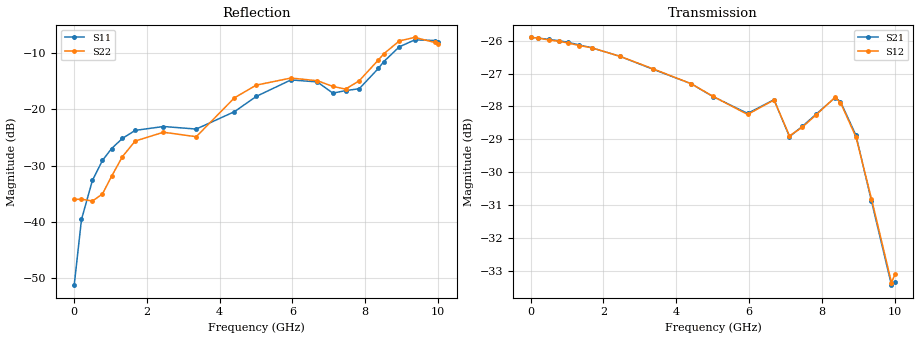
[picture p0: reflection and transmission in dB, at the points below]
! Device ID: PE43704
! Dir: z:\PE43704\PE43704_Char_1_20130516\PE43704\AMB\3p400V\25p00dB
! Serial: 14
! Insertion: A
! Impedance: 50 ohm
! Temp: Amb
! VDD: 3.400V
! Attenuation Step: 25.00dB
! IDD: 1.140097e-01mA
#  Hz  S  RI  R  50
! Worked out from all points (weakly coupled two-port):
!   401 points, 10 MHz to 10.01 GHz, reference 50 ohm
!   highest |S21| = -25.89 dB at 10 MHz (marker M1); lowest = -33.4 dB at 9.91 GHz (marker M2)
!   lowest |S11| = -51.3 dB at 10 MHz (marker M3), VSWR 1.01, Z = 50.3 + j0.0446 ohm
!   |S11| at or under -10 dB: start of sweep to 8.723 GHz
!   |S22| runs from -36.3 to -7.2 dB; largest |S21 - S12| = 0.00074
!   S11 on the Smith chart (normalised r, x): 10 MHz: 1.01, +0.00; 7.46 GHz: 0.78, +0.15; 8.51 GHz: 0.81, +0.46; 9.36 GHz: 0.54, +0.49; 10.01 GHz: 0.47, +0.28
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1e7  0.0027 0.000444  0.0507 -0.000144  0.0507 -0.000179  0.0158 0.000264
2.1e8  0.00142 0.0104  0.0505 -0.00281  0.0505 -0.00281  0.0142 0.00716
5.1e8  -0.00662 0.0224  0.0499 -0.00658  0.0498 -0.00663  0.0057 0.0142
7.85e8  -0.0194 0.0293  0.0491 -0.01  0.049 -0.01  -0.00708 0.0162
1.035e9  -0.0332 0.03  0.0481 -0.013  0.048 -0.0129  -0.0214 0.0136
1.335e9  -0.0487 0.0261  0.0466 -0.0163  0.0465 -0.0163  -0.0377 0.00519
1.685e9  -0.063 0.016  0.0446 -0.02  0.0446 -0.02  -0.0516 -0.00835
2.46e9  -0.0702 -0.00516  0.039 -0.027  0.039 -0.027  -0.057 -0.0259
3.36e9  -0.0668 0.000474  0.031 -0.0331  0.0311 -0.0331  -0.057 -0.00366
4.41e9  -0.0841 0.045  0.0221 -0.037  0.0221 -0.037  -0.1151 0.053
5.01e9  -0.1077 0.0736  0.0175 -0.0373  0.0178 -0.0372  -0.1505 0.0659
5.96e9  -0.1548 0.0969  0.0101 -0.0375  0.0103 -0.0373  -0.1731 0.0779
6.685e9  -0.1545 0.0831  0.00603 -0.0403  0.00576 -0.0403  -0.1571 0.0873
7.11e9  -0.1236 0.0644  -0.00041 -0.0358  -0.000427 -0.0359  -0.1174 0.1087
7.46e9  -0.1128 0.0939  0.000246 -0.0371  0.000374 -0.037  -0.083 0.1266
7.835e9  -0.0661 0.1375  -0.000827 -0.0387  -0.000914 -0.0386  -0.0604 0.1691
8.36e9  -0.0336 0.2286  -0.0104 -0.0397  -0.0102 -0.0398  -0.066 0.2668
8.51e9  -0.0365 0.2635  -0.0134 -0.0382  -0.013 -0.0382  -0.0749 0.3028
8.935e9  -0.0878 0.3486  -0.0184 -0.0309  -0.0185 -0.0306  -0.1324 0.3834
9.36e9  -0.1782 0.3747  -0.0164 -0.0234  -0.0168 -0.0234  -0.2074 0.384
9.91e9  -0.2953 0.2836  -0.00697 -0.0201  -0.00725 -0.0202  -0.301 0.2531
1.001e10  -0.3128 0.2502  -0.00503 -0.0209  -0.00522 -0.0215  -0.3121 0.2157
